VERSION 5.7 ;
  NOWIREEXTENSIONATPIN ON ;
  DIVIDERCHAR "/" ;
  BUSBITCHARS "[]" ;
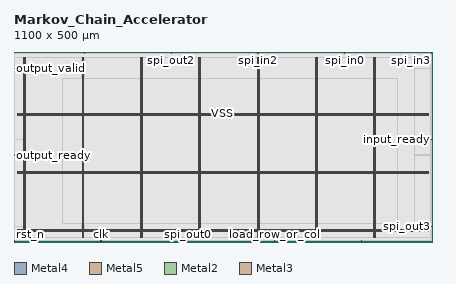
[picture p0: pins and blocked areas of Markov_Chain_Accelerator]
MACRO Markov_Chain_Accelerator
  CLASS BLOCK ;
  FOREIGN Markov_Chain_Accelerator ;
  ORIGIN 0.000 0.000 ;
  SIZE 1100.000 BY 500.000 ;
  PIN VDD
    DIRECTION INOUT ;
    USE POWER ;
    PORT
      LAYER Metal4 ;
        RECT 25.600 11.460 27.200 486.380 ;
    END
    PORT
      LAYER Metal4 ;
        RECT 179.200 11.460 180.800 486.380 ;
    END
    PORT
      LAYER Metal4 ;
        RECT 332.800 11.460 334.400 486.380 ;
    END
    PORT
      LAYER Metal4 ;
        RECT 486.400 11.460 488.000 486.380 ;
    END
    PORT
      LAYER Metal4 ;
        RECT 640.000 11.460 641.600 486.380 ;
    END
    PORT
      LAYER Metal4 ;
        RECT 793.600 11.460 795.200 486.380 ;
    END
    PORT
      LAYER Metal4 ;
        RECT 947.200 11.460 948.800 486.380 ;
    END
    PORT
      LAYER Metal5 ;
        RECT 9.780 27.610 1090.060 29.210 ;
    END
    PORT
      LAYER Metal5 ;
        RECT 9.780 180.790 1090.060 182.390 ;
    END
    PORT
      LAYER Metal5 ;
        RECT 9.780 333.970 1090.060 335.570 ;
    END
  END VDD
  PIN VSS
    DIRECTION INOUT ;
    USE GROUND ;
    PORT
      LAYER Metal4 ;
        RECT 28.900 11.460 30.500 486.380 ;
    END
    PORT
      LAYER Metal4 ;
        RECT 182.500 11.460 184.100 486.380 ;
    END
    PORT
      LAYER Metal4 ;
        RECT 336.100 11.460 337.700 486.380 ;
    END
    PORT
      LAYER Metal4 ;
        RECT 489.700 11.460 491.300 486.380 ;
    END
    PORT
      LAYER Metal4 ;
        RECT 643.300 11.460 644.900 486.380 ;
    END
    PORT
      LAYER Metal4 ;
        RECT 796.900 11.460 798.500 486.380 ;
    END
    PORT
      LAYER Metal4 ;
        RECT 950.500 11.460 952.100 486.380 ;
    END
    PORT
      LAYER Metal5 ;
        RECT 9.780 30.910 1090.060 32.510 ;
    END
    PORT
      LAYER Metal5 ;
        RECT 9.780 184.090 1090.060 185.690 ;
    END
    PORT
      LAYER Metal5 ;
        RECT 9.780 337.270 1090.060 338.870 ;
    END
  END VSS
  PIN clk
    DIRECTION INPUT ;
    USE SIGNAL ;
    ANTENNAGATEAREA 4.738000 ;
    PORT
      LAYER Metal2 ;
        RECT 228.480 0.000 229.040 4.000 ;
    END
  END clk
  PIN input_ready
    DIRECTION INPUT ;
    USE SIGNAL ;
    ANTENNAGATEAREA 1.102000 ;
    PORT
      LAYER Metal3 ;
        RECT 1096.000 268.800 1100.000 269.360 ;
    END
  END input_ready
  PIN load_row_or_col
    DIRECTION INPUT ;
    USE SIGNAL ;
    ANTENNAGATEAREA 2.204000 ;
    PORT
      LAYER Metal2 ;
        RECT 685.440 0.000 686.000 4.000 ;
    END
  END load_row_or_col
  PIN output_ready
    DIRECTION OUTPUT TRISTATE ;
    USE SIGNAL ;
    ANTENNADIFFAREA 1.986000 ;
    PORT
      LAYER Metal3 ;
        RECT 0.000 228.480 4.000 229.040 ;
    END
  END output_ready
  PIN output_valid
    DIRECTION INPUT ;
    USE SIGNAL ;
    ANTENNAGATEAREA 0.726000 ;
    PORT
      LAYER Metal3 ;
        RECT 0.000 456.960 4.000 457.520 ;
    END
  END output_valid
  PIN rst_n
    DIRECTION INPUT ;
    USE SIGNAL ;
    ANTENNAGATEAREA 1.102000 ;
    PORT
      LAYER Metal2 ;
        RECT 0.000 0.000 0.560 4.000 ;
    END
  END rst_n
  PIN spi_in0
    DIRECTION INPUT ;
    USE SIGNAL ;
    ANTENNAGATEAREA 2.204000 ;
    PORT
      LAYER Metal2 ;
        RECT 870.240 496.000 870.800 500.000 ;
    END
  END spi_in0
  PIN spi_in1
    DIRECTION INPUT ;
    USE SIGNAL ;
    ANTENNAGATEAREA 2.204000 ;
    PORT
      LAYER Metal2 ;
        RECT 913.920 0.000 914.480 4.000 ;
    END
  END spi_in1
  PIN spi_in2
    DIRECTION INPUT ;
    USE SIGNAL ;
    ANTENNAGATEAREA 2.204000 ;
    PORT
      LAYER Metal2 ;
        RECT 641.760 496.000 642.320 500.000 ;
    END
  END spi_in2
  PIN spi_in3
    DIRECTION INPUT ;
    USE SIGNAL ;
    ANTENNAGATEAREA 2.204000 ;
    PORT
      LAYER Metal2 ;
        RECT 1098.720 496.000 1099.280 500.000 ;
    END
  END spi_in3
  PIN spi_out0
    DIRECTION OUTPUT TRISTATE ;
    USE SIGNAL ;
    ANTENNADIFFAREA 2.080400 ;
    PORT
      LAYER Metal2 ;
        RECT 456.960 0.000 457.520 4.000 ;
    END
  END spi_out0
  PIN spi_out1
    DIRECTION OUTPUT TRISTATE ;
    USE SIGNAL ;
    ANTENNADIFFAREA 1.986000 ;
    PORT
      LAYER Metal2 ;
        RECT 184.800 496.000 185.360 500.000 ;
    END
  END spi_out1
  PIN spi_out2
    DIRECTION OUTPUT TRISTATE ;
    USE SIGNAL ;
    ANTENNADIFFAREA 1.986000 ;
    PORT
      LAYER Metal2 ;
        RECT 413.280 496.000 413.840 500.000 ;
    END
  END spi_out2
  PIN spi_out3
    DIRECTION OUTPUT TRISTATE ;
    USE SIGNAL ;
    ANTENNADIFFAREA 1.986000 ;
    PORT
      LAYER Metal3 ;
        RECT 1096.000 40.320 1100.000 40.880 ;
    END
  END spi_out3
  OBS
      LAYER Metal1 ;
        RECT 10.080 10.790 1099.190 487.050 ;
      LAYER Metal2 ;
        RECT 0.140 495.700 184.500 496.000 ;
        RECT 185.660 495.700 412.980 496.000 ;
        RECT 414.140 495.700 641.460 496.000 ;
        RECT 642.620 495.700 869.940 496.000 ;
        RECT 871.100 495.700 1098.420 496.000 ;
        RECT 0.140 4.300 1099.140 495.700 ;
        RECT 0.860 4.000 228.180 4.300 ;
        RECT 229.340 4.000 456.660 4.300 ;
        RECT 457.820 4.000 685.140 4.300 ;
        RECT 686.300 4.000 913.620 4.300 ;
        RECT 914.780 4.000 1099.140 4.300 ;
      LAYER Metal3 ;
        RECT 0.090 457.820 1096.000 486.220 ;
        RECT 4.300 456.660 1096.000 457.820 ;
        RECT 0.090 269.660 1096.000 456.660 ;
        RECT 0.090 268.500 1095.700 269.660 ;
        RECT 0.090 229.340 1096.000 268.500 ;
        RECT 4.300 228.180 1096.000 229.340 ;
        RECT 0.090 41.180 1096.000 228.180 ;
        RECT 0.090 40.020 1095.700 41.180 ;
        RECT 0.090 11.620 1096.000 40.020 ;
      LAYER Metal4 ;
        RECT 27.580 33.690 28.600 484.310 ;
        RECT 30.800 33.690 178.900 484.310 ;
        RECT 181.100 33.690 182.200 484.310 ;
        RECT 184.400 33.690 332.500 484.310 ;
        RECT 334.700 33.690 335.800 484.310 ;
        RECT 338.000 33.690 486.100 484.310 ;
        RECT 488.300 33.690 489.400 484.310 ;
        RECT 491.600 33.690 639.700 484.310 ;
        RECT 641.900 33.690 643.000 484.310 ;
        RECT 645.200 33.690 793.300 484.310 ;
        RECT 795.500 33.690 796.600 484.310 ;
        RECT 798.800 33.690 946.900 484.310 ;
        RECT 949.100 33.690 950.200 484.310 ;
        RECT 952.400 33.690 1053.780 484.310 ;
      LAYER Metal5 ;
        RECT 126.620 339.470 1009.060 429.970 ;
        RECT 126.620 336.170 1009.060 336.670 ;
        RECT 126.620 186.290 1009.060 333.370 ;
        RECT 126.620 182.990 1009.060 183.490 ;
        RECT 126.620 49.730 1009.060 180.190 ;
  END
END Markov_Chain_Accelerator
END LIBRARY

